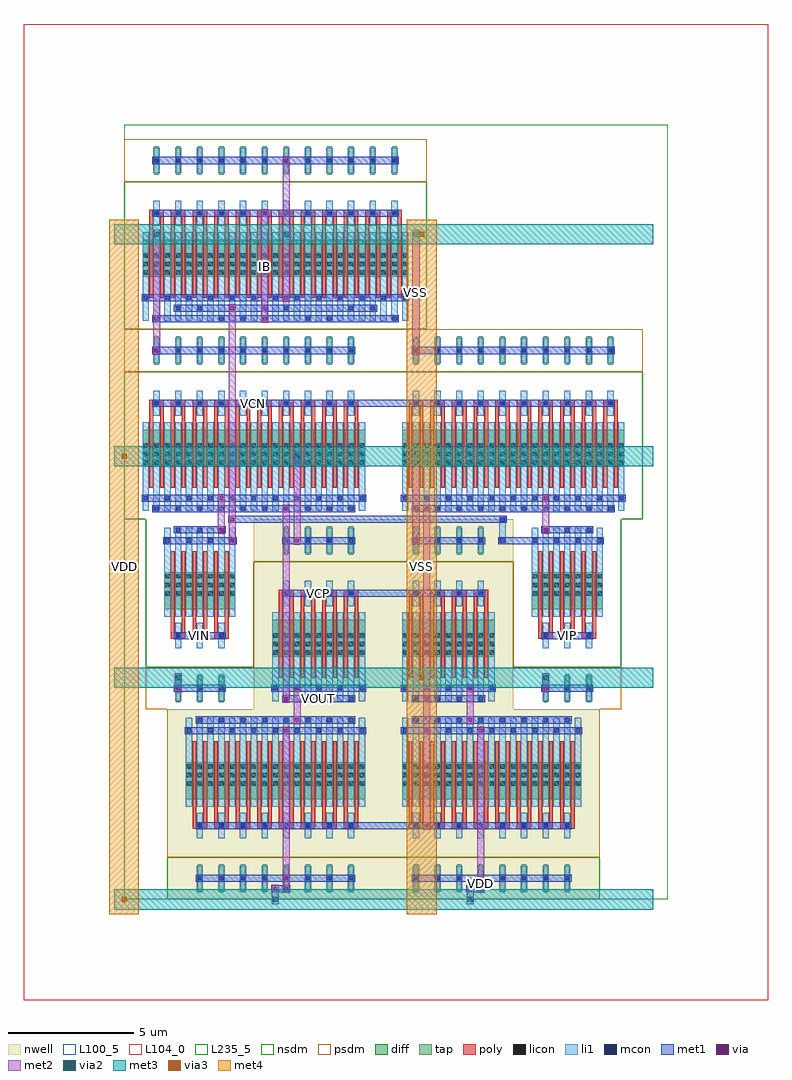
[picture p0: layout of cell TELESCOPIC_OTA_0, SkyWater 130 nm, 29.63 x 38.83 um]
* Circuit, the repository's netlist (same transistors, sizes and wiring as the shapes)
* NGSPICE file created from TELESCOPIC_OTA_0.ext - technology: sky130A

.subckt PMOS_4T_48128194_X4_Y1_1774869455 a_230_420# a_200_252# a_147_420# w_0_0#
X0 a_230_420# a_200_252# a_147_420# w_0_0# sky130_fd_pr__pfet_01v8 ad=0.2058 pd=1.75 as=0.2058 ps=1.75 w=1.47 l=0.15 M=8
.ends

.subckt NMOS_4T_31167546_X10_Y1_1774869453 a_230_420# a_200_252# a_147_420# a_241_1232#
X0 a_147_420# a_200_252# a_230_420# a_241_1232# sky130_fd_pr__nfet_01v8 ad=0.2058 pd=1.75 as=0.2058 ps=1.75 w=1.47 l=0.15 M=20
.ends

.subckt SCM_NMOS_90644832_X6_Y1_1774869457 a_402_420# a_200_252# a_147_420#
X0 a_147_420# a_200_252# a_402_420# a_147_420# sky130_fd_pr__nfet_01v8 ad=0.2058 pd=1.75 as=0.2058 ps=1.75 w=1.47 l=0.15 M=12
X1 a_147_420# a_200_252# a_200_252# a_147_420# sky130_fd_pr__nfet_01v8 ad=0.2058 pd=1.75 as=0.2058 ps=1.75 w=1.47 l=0.15 M=12
.ends

.subckt NMOS_4T_47642139_X3_Y1_1774869454 a_230_420# a_200_252# a_147_420# a_241_1232#
X0 a_147_420# a_200_252# a_230_420# a_241_1232# sky130_fd_pr__nfet_01v8 ad=0.2058 pd=1.75 as=0.2058 ps=1.75 w=1.47 l=0.15 M=6
.ends

.subckt PMOS_S_59459431_X8_Y1_1774869456 a_230_420# a_200_252# w_0_0#
X0 a_230_420# a_200_252# w_0_0# w_0_0# sky130_fd_pr__pfet_01v8 ad=0.2058 pd=1.75 as=0.2058 ps=1.75 w=1.47 l=0.15 M=16
.ends

.subckt TELESCOPIC_OTA_0 IB VCN VOUT VIP VIN VCP VSS VDD
XPMOS_4T_48128194_X4_Y1_1774869455_1 m1_2376_560# VCP m1_2720_1400# VDD PMOS_4T_48128194_X4_Y1_1774869455
XPMOS_4T_48128194_X4_Y1_1774869455_0 VOUT VCP m1_1344_1400# VDD PMOS_4T_48128194_X4_Y1_1774869455
XNMOS_4T_31167546_X10_Y1_1774869453_0 VOUT VCN m1_742_2912# VSS NMOS_4T_31167546_X10_Y1_1774869453
XNMOS_4T_31167546_X10_Y1_1774869453_1 m1_2376_560# VCN m1_3322_2912# VSS NMOS_4T_31167546_X10_Y1_1774869453
XSCM_NMOS_90644832_X6_Y1_1774869457_0 li_2985_2839# IB VSS SCM_NMOS_90644832_X6_Y1_1774869457
XNMOS_4T_47642139_X3_Y1_1774869454_0 m1_742_2912# VIN li_2985_2839# VSS NMOS_4T_47642139_X3_Y1_1774869454
XNMOS_4T_47642139_X3_Y1_1774869454_1 m1_3322_2912# VIP li_2985_2839# VSS NMOS_4T_47642139_X3_Y1_1774869454
XPMOS_S_59459431_X8_Y1_1774869456_0 m1_1344_1400# m1_2376_560# VDD PMOS_S_59459431_X8_Y1_1774869456
XPMOS_S_59459431_X8_Y1_1774869456_1 m1_2720_1400# m1_2376_560# VDD PMOS_S_59459431_X8_Y1_1774869456
.ends

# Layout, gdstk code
from math import pi, radians
import gdstk
lib = gdstk.Library(unit=1e-6, precision=1e-09)
def R(c, l, rs):  # rectangles x0, y0, x1, y1
    for r in rs: c.add(gdstk.rectangle(r[:2], r[2:], *l))
def A(c, l, x, y, w, h, nx, ny, dx, dy):  # array of equal rectangles
    R(c, l, [(x+i*dx, y+j*dy, x+i*dx+w, y+j*dy+h) for i in range(nx) for j in range(ny)])
def P(c, l, *ps):  # polygons
    for p in ps: c.add(gdstk.Polygon(p, *l))
nwell = (64, 20)
diff = (65, 20)
tap = (65, 44)
poly = (66, 20)
licon = (66, 44)
li1 = (67, 20)
mcon = (67, 44)
met1 = (68, 20)
via = (68, 44)
met2 = (69, 20)
via2 = (69, 44)
met3 = (70, 20)
via3 = (70, 44)
met4 = (71, 20)
nsdm = (93, 44)
psdm = (94, 20)
L100_5 = (100, 5)
L104_0 = (104, 0)
L235_5 = (235, 5)

scm_nmos_90644832_x6_y1_ = lib.new_cell('SCM_NMOS_90644832_X6_Y1_1774869457')
R(scm_nmos_90644832_x6_y1_, diff, [(0.735,2.1,11.305,3.57)])
A(scm_nmos_90644832_x6_y1_, tap, 1.205, 6.16, 0.17, 1.12, 12, 1, 0.86, 0)
A(scm_nmos_90644832_x6_y1_, poly, 1, 1.26, 0.15, 3.36, 24, 1, 0.43, 0)
A(scm_nmos_90644832_x6_y1_, poly, 1, 4.485, 0.58, 0.27, 12, 1, 0.86, 0)
A(scm_nmos_90644832_x6_y1_, licon, 0.775, 2.18, 0.17, 0.17, 3, 3, 0.43, 0.34)
A(scm_nmos_90644832_x6_y1_, licon, 1.635, 2.18, 0.17, 0.17, 3, 3, 0.43, 0.34)
A(scm_nmos_90644832_x6_y1_, licon, 2.495, 2.18, 0.17, 0.17, 3, 3, 0.43, 0.34)
A(scm_nmos_90644832_x6_y1_, licon, 3.355, 2.18, 0.17, 0.17, 3, 3, 0.43, 0.34)
A(scm_nmos_90644832_x6_y1_, licon, 4.215, 2.18, 0.17, 0.17, 3, 3, 0.43, 0.34)
A(scm_nmos_90644832_x6_y1_, licon, 5.075, 2.18, 0.17, 0.17, 3, 3, 0.43, 0.34)
A(scm_nmos_90644832_x6_y1_, licon, 5.935, 2.18, 0.17, 0.17, 3, 3, 0.43, 0.34)
A(scm_nmos_90644832_x6_y1_, licon, 6.795, 2.18, 0.17, 0.17, 3, 3, 0.43, 0.34)
A(scm_nmos_90644832_x6_y1_, licon, 7.655, 2.18, 0.17, 0.17, 3, 3, 0.43, 0.34)
A(scm_nmos_90644832_x6_y1_, licon, 8.515, 2.18, 0.17, 0.17, 3, 3, 0.43, 0.34)
A(scm_nmos_90644832_x6_y1_, licon, 9.375, 2.18, 0.17, 0.17, 3, 3, 0.43, 0.34)
A(scm_nmos_90644832_x6_y1_, licon, 10.235, 2.18, 0.17, 0.17, 3, 3, 0.43, 0.34)
A(scm_nmos_90644832_x6_y1_, licon, 1.205, 4.535, 0.17, 0.17, 12, 2, 0.86, 2.1)
A(scm_nmos_90644832_x6_y1_, li1, 0.735, 0.335, 0.25, 3.53, 25, 1, 0.43, 0)
A(scm_nmos_90644832_x6_y1_, li1, 1.165, 4.115, 0.25, 1.01, 12, 2, 0.86, 2.1)
A(scm_nmos_90644832_x6_y1_, mcon, 0.775, 1.175, 0.17, 0.17, 13, 1, 0.86, 0)
A(scm_nmos_90644832_x6_y1_, mcon, 1.205, 4.535, 0.17, 0.17, 12, 2, 0.86, 2.1)
R(scm_nmos_90644832_x6_y1_, mcon, [(1.205,0.335,1.375,0.505), (3.785,0.335,3.955,0.505), (4.645,0.335,4.815,0.505), (7.225,0.335,7.395,0.505), (8.085,0.335,8.255,0.505), (10.665,0.335,10.835,0.505), (2.065,0.755,2.235,0.925), (2.925,0.755,3.095,0.925), (5.505,0.755,5.675,0.925), (6.365,0.755,6.535,0.925), (8.945,0.755,9.115,0.925), (9.805,0.755,9.975,0.925)])
R(scm_nmos_90644832_x6_y1_, met1, [(1.12,0.28,10.92,0.56), (1.98,0.7,10.06,0.98), (0.69,1.12,11.35,1.4), (1.12,4.48,10.92,4.76), (1.12,6.58,10.92,6.86)])
R(scm_nmos_90644832_x6_y1_, via, [(5.515,0.345,5.665,0.495), (6.375,1.185,6.525,1.335), (5.515,4.545,5.665,4.695), (6.375,6.645,6.525,6.795)])
R(scm_nmos_90644832_x6_y1_, met2, [(5.45,0.26,5.73,4.78), (6.31,1.1,6.59,6.88)])
R(scm_nmos_90644832_x6_y1_, nsdm, [(0,0,12.04,5.88)])
R(scm_nmos_90644832_x6_y1_, psdm, [(0,5.88,12.04,7.56)])
R(scm_nmos_90644832_x6_y1_, L100_5, [(0,0,12.04,7.56)])

pmos_s_59459431_x8_y1_17 = lib.new_cell('PMOS_S_59459431_X8_Y1_1774869456')
R(pmos_s_59459431_x8_y1_17, nwell, [(0,0,8.6,7.56)])
R(pmos_s_59459431_x8_y1_17, diff, [(0.735,2.1,7.865,3.57)])
A(pmos_s_59459431_x8_y1_17, tap, 1.205, 6.16, 0.17, 1.12, 8, 1, 0.86, 0)
A(pmos_s_59459431_x8_y1_17, poly, 1, 1.26, 0.15, 3.36, 16, 1, 0.43, 0)
A(pmos_s_59459431_x8_y1_17, poly, 1, 4.485, 0.58, 0.27, 8, 1, 0.86, 0)
A(pmos_s_59459431_x8_y1_17, licon, 0.775, 2.18, 0.17, 0.17, 3, 3, 0.43, 0.34)
A(pmos_s_59459431_x8_y1_17, licon, 1.635, 2.18, 0.17, 0.17, 3, 3, 0.43, 0.34)
A(pmos_s_59459431_x8_y1_17, licon, 2.495, 2.18, 0.17, 0.17, 3, 3, 0.43, 0.34)
A(pmos_s_59459431_x8_y1_17, licon, 3.355, 2.18, 0.17, 0.17, 3, 3, 0.43, 0.34)
A(pmos_s_59459431_x8_y1_17, licon, 4.215, 2.18, 0.17, 0.17, 3, 3, 0.43, 0.34)
A(pmos_s_59459431_x8_y1_17, licon, 5.075, 2.18, 0.17, 0.17, 3, 3, 0.43, 0.34)
A(pmos_s_59459431_x8_y1_17, licon, 5.935, 2.18, 0.17, 0.17, 3, 3, 0.43, 0.34)
A(pmos_s_59459431_x8_y1_17, licon, 6.795, 2.18, 0.17, 0.17, 3, 3, 0.43, 0.34)
A(pmos_s_59459431_x8_y1_17, licon, 1.205, 4.535, 0.17, 0.17, 8, 2, 0.86, 2.1)
A(pmos_s_59459431_x8_y1_17, li1, 0.735, 0.335, 0.25, 3.53, 17, 1, 0.43, 0)
A(pmos_s_59459431_x8_y1_17, li1, 1.165, 4.115, 0.25, 1.01, 8, 2, 0.86, 2.1)
A(pmos_s_59459431_x8_y1_17, mcon, 1.205, 0.335, 0.17, 0.17, 8, 2, 0.86, 4.2)
A(pmos_s_59459431_x8_y1_17, mcon, 0.775, 0.755, 0.17, 0.17, 9, 1, 0.86, 0)
A(pmos_s_59459431_x8_y1_17, mcon, 1.205, 6.635, 0.17, 0.17, 8, 1, 0.86, 0)
R(pmos_s_59459431_x8_y1_17, met1, [(1.12,0.28,7.48,0.56), (0.69,0.7,7.91,0.98), (1.12,4.48,7.48,4.76), (1.12,6.58,7.48,6.86)])
R(pmos_s_59459431_x8_y1_17, via, [(4.655,0.765,4.805,0.915), (4.655,6.645,4.805,6.795)])
R(pmos_s_59459431_x8_y1_17, met2, [(4.59,0.68,4.87,6.88)])
R(pmos_s_59459431_x8_y1_17, nsdm, [(0,5.88,8.6,7.56)])
R(pmos_s_59459431_x8_y1_17, psdm, [(0,0,8.6,5.88)])
R(pmos_s_59459431_x8_y1_17, L100_5, [(0,0,8.6,7.56)])

nmos_4t_31167546_x10_y1_ = lib.new_cell('NMOS_4T_31167546_X10_Y1_1774869453')
R(nmos_4t_31167546_x10_y1_, diff, [(0.735,2.1,9.585,3.57)])
A(nmos_4t_31167546_x10_y1_, tap, 1.205, 6.16, 0.17, 1.12, 10, 1, 0.86, 0)
A(nmos_4t_31167546_x10_y1_, poly, 1, 1.26, 0.15, 3.36, 20, 1, 0.43, 0)
A(nmos_4t_31167546_x10_y1_, poly, 1, 4.485, 0.58, 0.27, 10, 1, 0.86, 0)
A(nmos_4t_31167546_x10_y1_, licon, 0.775, 2.18, 0.17, 0.17, 3, 3, 0.43, 0.34)
A(nmos_4t_31167546_x10_y1_, licon, 1.635, 2.18, 0.17, 0.17, 3, 3, 0.43, 0.34)
A(nmos_4t_31167546_x10_y1_, licon, 2.495, 2.18, 0.17, 0.17, 3, 3, 0.43, 0.34)
A(nmos_4t_31167546_x10_y1_, licon, 3.355, 2.18, 0.17, 0.17, 3, 3, 0.43, 0.34)
A(nmos_4t_31167546_x10_y1_, licon, 4.215, 2.18, 0.17, 0.17, 3, 3, 0.43, 0.34)
A(nmos_4t_31167546_x10_y1_, licon, 5.075, 2.18, 0.17, 0.17, 3, 3, 0.43, 0.34)
A(nmos_4t_31167546_x10_y1_, licon, 5.935, 2.18, 0.17, 0.17, 3, 3, 0.43, 0.34)
A(nmos_4t_31167546_x10_y1_, licon, 6.795, 2.18, 0.17, 0.17, 3, 3, 0.43, 0.34)
A(nmos_4t_31167546_x10_y1_, licon, 7.655, 2.18, 0.17, 0.17, 3, 3, 0.43, 0.34)
A(nmos_4t_31167546_x10_y1_, licon, 8.515, 2.18, 0.17, 0.17, 3, 3, 0.43, 0.34)
A(nmos_4t_31167546_x10_y1_, licon, 1.205, 4.535, 0.17, 0.17, 10, 2, 0.86, 2.1)
A(nmos_4t_31167546_x10_y1_, li1, 0.735, 0.335, 0.25, 3.53, 21, 1, 0.43, 0)
A(nmos_4t_31167546_x10_y1_, li1, 1.165, 4.115, 0.25, 1.01, 10, 2, 0.86, 2.1)
A(nmos_4t_31167546_x10_y1_, mcon, 1.205, 0.335, 0.17, 0.17, 10, 2, 0.86, 4.2)
A(nmos_4t_31167546_x10_y1_, mcon, 0.775, 0.755, 0.17, 0.17, 11, 1, 0.86, 0)
A(nmos_4t_31167546_x10_y1_, mcon, 1.205, 6.635, 0.17, 0.17, 10, 1, 0.86, 0)
R(nmos_4t_31167546_x10_y1_, met1, [(1.12,0.28,9.2,0.56), (0.69,0.7,9.63,0.98), (1.12,4.48,9.2,4.76), (1.12,6.58,9.2,6.86)])
R(nmos_4t_31167546_x10_y1_, nsdm, [(0,0,10.32,5.88)])
R(nmos_4t_31167546_x10_y1_, psdm, [(0,5.88,10.32,7.56)])
R(nmos_4t_31167546_x10_y1_, L100_5, [(0,0,10.32,7.56)])

nmos_4t_47642139_x3_y1_1 = lib.new_cell('NMOS_4T_47642139_X3_Y1_1774869454')
R(nmos_4t_47642139_x3_y1_1, diff, [(0.735,2.1,3.565,3.57)])
A(nmos_4t_47642139_x3_y1_1, tap, 1.205, 6.16, 0.17, 1.12, 3, 1, 0.86, 0)
A(nmos_4t_47642139_x3_y1_1, poly, 1, 1.26, 0.15, 3.36, 6, 1, 0.43, 0)
A(nmos_4t_47642139_x3_y1_1, poly, 1, 4.485, 0.58, 0.27, 3, 1, 0.86, 0)
A(nmos_4t_47642139_x3_y1_1, licon, 0.775, 2.18, 0.17, 0.17, 3, 3, 0.43, 0.34)
A(nmos_4t_47642139_x3_y1_1, licon, 1.635, 2.18, 0.17, 0.17, 3, 3, 0.43, 0.34)
A(nmos_4t_47642139_x3_y1_1, licon, 2.495, 2.18, 0.17, 0.17, 3, 3, 0.43, 0.34)
A(nmos_4t_47642139_x3_y1_1, licon, 1.205, 4.535, 0.17, 0.17, 3, 2, 0.86, 2.1)
A(nmos_4t_47642139_x3_y1_1, li1, 0.735, 0.335, 0.25, 3.53, 7, 1, 0.43, 0)
A(nmos_4t_47642139_x3_y1_1, li1, 1.165, 4.115, 0.25, 1.01, 3, 2, 0.86, 2.1)
A(nmos_4t_47642139_x3_y1_1, mcon, 1.205, 0.335, 0.17, 0.17, 3, 2, 0.86, 4.2)
A(nmos_4t_47642139_x3_y1_1, mcon, 0.775, 0.755, 0.17, 0.17, 4, 1, 0.86, 0)
A(nmos_4t_47642139_x3_y1_1, mcon, 1.205, 6.635, 0.17, 0.17, 3, 1, 0.86, 0)
R(nmos_4t_47642139_x3_y1_1, met1, [(1.12,0.28,3.18,0.56), (0.69,0.7,3.61,0.98), (1.12,4.48,3.18,4.76), (1.12,6.58,3.18,6.86)])
R(nmos_4t_47642139_x3_y1_1, nsdm, [(0,0,4.3,5.88)])
R(nmos_4t_47642139_x3_y1_1, psdm, [(0,5.88,4.3,7.56)])
R(nmos_4t_47642139_x3_y1_1, L100_5, [(0,0,4.3,7.56)])

pmos_4t_48128194_x4_y1_1 = lib.new_cell('PMOS_4T_48128194_X4_Y1_1774869455')
R(pmos_4t_48128194_x4_y1_1, nwell, [(0,0,5.16,7.56)])
R(pmos_4t_48128194_x4_y1_1, diff, [(0.735,2.1,4.425,3.57)])
A(pmos_4t_48128194_x4_y1_1, tap, 1.205, 6.16, 0.17, 1.12, 4, 1, 0.86, 0)
A(pmos_4t_48128194_x4_y1_1, poly, 1, 1.26, 0.15, 3.36, 8, 1, 0.43, 0)
A(pmos_4t_48128194_x4_y1_1, poly, 1, 4.485, 0.58, 0.27, 4, 1, 0.86, 0)
A(pmos_4t_48128194_x4_y1_1, licon, 0.775, 2.18, 0.17, 0.17, 3, 3, 0.43, 0.34)
A(pmos_4t_48128194_x4_y1_1, licon, 1.635, 2.18, 0.17, 0.17, 3, 3, 0.43, 0.34)
A(pmos_4t_48128194_x4_y1_1, licon, 2.495, 2.18, 0.17, 0.17, 3, 3, 0.43, 0.34)
A(pmos_4t_48128194_x4_y1_1, licon, 3.355, 2.18, 0.17, 0.17, 3, 3, 0.43, 0.34)
A(pmos_4t_48128194_x4_y1_1, licon, 1.205, 4.535, 0.17, 0.17, 4, 2, 0.86, 2.1)
A(pmos_4t_48128194_x4_y1_1, li1, 0.735, 0.335, 0.25, 3.53, 9, 1, 0.43, 0)
A(pmos_4t_48128194_x4_y1_1, li1, 1.165, 4.115, 0.25, 1.01, 4, 2, 0.86, 2.1)
A(pmos_4t_48128194_x4_y1_1, mcon, 1.205, 0.335, 0.17, 0.17, 4, 2, 0.86, 4.2)
A(pmos_4t_48128194_x4_y1_1, mcon, 0.775, 0.755, 0.17, 0.17, 5, 1, 0.86, 0)
A(pmos_4t_48128194_x4_y1_1, mcon, 1.205, 6.635, 0.17, 0.17, 4, 1, 0.86, 0)
R(pmos_4t_48128194_x4_y1_1, met1, [(1.12,0.28,4.04,0.56), (0.69,0.7,4.47,0.98), (1.12,4.48,4.04,4.76), (1.12,6.58,4.04,6.86)])
R(pmos_4t_48128194_x4_y1_1, nsdm, [(0,5.88,5.16,7.56)])
R(pmos_4t_48128194_x4_y1_1, psdm, [(0,0,5.16,5.88)])
R(pmos_4t_48128194_x4_y1_1, L100_5, [(0,0,5.16,7.56)])

telescopic_ota_0 = lib.new_cell('TELESCOPIC_OTA_0')
R(telescopic_ota_0, li1, [(14.925,14.195,15.175,14.365), (14.925,14.195,15.175,14.365), (14.925,14.28,15.175,15.12), (14.925,15.035,15.175,15.205), (14.925,15.035,15.175,15.205)])
R(telescopic_ota_0, mcon, [(14.965,14.195,15.135,14.365), (14.965,14.195,15.135,14.365), (14.965,15.035,15.135,15.205), (14.965,15.035,15.135,15.205)])
R(telescopic_ota_0, met1, [(5.86,0.28,6.18,0.56), (5.86,0.28,6.18,0.56), (5.86,0.28,6.18,0.56), (5.86,0.28,6.18,0.56), (6.02,0.28,6.45,0.56), (6.29,0.28,6.61,0.56), (6.29,0.28,6.61,0.56), (6.29,0.28,6.61,0.56), (6.29,0.28,6.61,0.56), (13.6,0.28,13.92,0.56), (13.6,0.28,13.92,0.56), (13.6,0.28,13.92,0.56), (13.6,0.28,13.92,0.56), (13.6,0.28,13.92,0.56), (13.76,0.28,14.19,0.56), (14.03,0.28,14.35,0.56), (14.03,0.28,14.35,0.56), (14.03,0.28,14.35,0.56), (14.03,0.28,14.35,0.56), (14.03,0.28,14.35,0.56), (9.03,2.8,11.61,3.08), (11.88,2.8,12.2,3.08), (11.88,2.8,12.2,3.08), (11.88,2.8,12.2,3.08), (11.88,2.8,12.2,3.08), (6.72,7,7.04,7.28), (6.72,7,7.04,7.28), (13.6,7,13.92,7.28), (13.6,7,13.92,7.28), (6.29,7.84,6.61,8.12), (6.29,7.84,6.61,8.12), (11.88,7.84,12.2,8.12), (11.88,7.84,12.2,8.12), (11.88,7.84,12.2,8.12), (11.88,7.84,12.2,8.12), (1.99,8.26,2.31,8.54), (1.99,8.26,2.31,8.54), (6.72,8.26,7.04,8.54), (6.72,8.26,7.04,8.54), (13.6,8.26,13.92,8.54), (13.6,8.26,13.92,8.54), (16.61,8.26,16.93,8.54), (16.61,8.26,16.93,8.54), (16.61,8.26,16.93,8.54), (9.03,12.04,11.61,12.32), (4.14,14.14,4.46,14.42), (4.14,14.14,4.46,14.42), (4.14,14.14,4.46,14.42), (4.14,14.14,4.46,14.42), (6.72,14.14,7.04,14.42), (6.72,14.14,7.04,14.42), (11.45,14.14,11.77,14.42), (11.45,14.14,11.77,14.42), (11.45,14.14,11.77,14.42), (14.88,14.14,15.22,14.42), (14.88,14.14,15.22,14.42), (15.05,14.14,16.34,14.42), (3.71,14.56,4.03,14.84), (3.71,14.56,4.03,14.84), (16.61,14.56,16.93,14.84), (16.61,14.56,16.93,14.84), (4.14,14.98,4.46,15.26), (4.14,14.98,4.46,15.26), (4.3,14.98,15.05,15.26), (14.88,14.98,15.22,15.26), (14.88,14.98,15.22,15.26), (6.29,15.4,6.61,15.68), (6.29,15.4,6.61,15.68), (11.88,15.4,12.2,15.68), (11.88,15.4,12.2,15.68), (3.71,15.82,4.03,16.1), (3.71,15.82,4.03,16.1), (16.61,15.82,16.93,16.1), (16.61,15.82,16.93,16.1), (9.03,19.6,11.61,19.88), (1.13,21.7,1.45,21.98), (1.13,21.7,1.45,21.98), (1.13,21.7,1.45,21.98), (1.13,21.7,1.45,21.98), (11.45,21.7,11.77,21.98), (11.45,21.7,11.77,21.98), (11.45,21.7,11.77,21.98), (11.45,21.7,11.77,21.98), (11.45,21.7,11.77,21.98), (4.14,23.38,4.46,23.66), (4.14,23.38,4.46,23.66), (4.14,23.38,4.46,23.66), (4.14,23.38,4.46,23.66)])
P(telescopic_ota_0, met1, [(0,0),(0,0),(0,0),(0,0)],
  [(0,0),(0,0),(0,0),(0,0)],
  [(0,0),(0,0),(0,0),(0,0)],
  [(0,0),(0,0),(0,0),(0,0)],
  [(0,0),(0,0),(0,0),(0,0)],
  [(0,0),(0,0),(0,0),(0,0)],
  [(0,0),(0,0),(0,0),(0,0)],
  [(0,0),(0,0),(0,0),(0,0)],
  [(0,0),(0,0),(0,0),(0,0)],
  [(0,0),(0,0),(0,0),(0,0)],
  [(0,0),(0,0),(0,0),(0,0)],
  [(0,0),(0,0),(0,0),(0,0)],
  [(0,0),(0,0),(0,0),(0,0)],
  [(0,0),(0,0),(0,0),(0,0)],
  [(0,0),(0,0),(0,0),(0,0)],
  [(0,0),(0,0),(0,0),(0,0)],
  [(0,0),(0,0),(0,0),(0,0)],
  [(0,0),(0,0),(0,0),(0,0)],
  [(0,0),(0,0),(0,0),(0,0)],
  [(0,0),(0,0),(0,0),(0,0)],
  [(0,0),(0,0),(0,0),(0,0)],
  [(0,0),(0,0),(0,0),(0,0)],
  [(0,0),(0,0),(0,0),(0,0)],
  [(0,0),(0,0),(0,0),(0,0)],
  [(0,0),(0,0),(0,0),(0,0)],
  [(0,0),(0,0),(0,0),(0,0)],
  [(0,0),(0,0),(0,0),(0,0)],
  [(0,0),(0,0),(0,0),(0,0)],
  [(0,0),(0,0),(0,0),(0,0)],
  [(0,0),(0,0),(0,0),(0,0)],
  [(0,0),(0,0),(0,0),(0,0)],
  [(0,0),(0,0),(0,0),(0,0)],
  [(0,0),(0,0),(0,0),(0,0)],
  [(0,0),(0,0),(0,0),(0,0)])
R(telescopic_ota_0, via, [(5.945,0.345,6.095,0.495), (5.945,0.345,6.095,0.495), (5.945,0.345,6.095,0.495), (5.945,0.345,6.095,0.495), (6.375,0.345,6.525,0.495), (6.375,0.345,6.525,0.495), (6.375,0.345,6.525,0.495), (6.375,0.345,6.525,0.495), (13.685,0.345,13.835,0.495), (13.685,0.345,13.835,0.495), (13.685,0.345,13.835,0.495), (13.685,0.345,13.835,0.495), (13.685,0.345,13.835,0.495), (14.115,0.345,14.265,0.495), (14.115,0.345,14.265,0.495), (14.115,0.345,14.265,0.495), (14.115,0.345,14.265,0.495), (14.115,0.345,14.265,0.495), (11.965,2.865,12.115,3.015), (11.965,2.865,12.115,3.015), (11.965,2.865,12.115,3.015), (11.965,2.865,12.115,3.015), (6.805,7.065,6.955,7.215), (6.805,7.065,6.955,7.215), (13.685,7.065,13.835,7.215), (13.685,7.065,13.835,7.215), (6.375,7.905,6.525,8.055), (6.375,7.905,6.525,8.055), (11.965,7.905,12.115,8.055), (11.965,7.905,12.115,8.055), (11.965,7.905,12.115,8.055), (11.965,7.905,12.115,8.055), (2.075,8.325,2.225,8.475), (2.075,8.325,2.225,8.475), (6.805,8.325,6.955,8.475), (6.805,8.325,6.955,8.475), (13.685,8.325,13.835,8.475), (13.685,8.325,13.835,8.475), (16.695,8.325,16.845,8.475), (16.695,8.325,16.845,8.475), (16.695,8.325,16.845,8.475), (4.225,14.205,4.375,14.355), (4.225,14.205,4.375,14.355), (4.225,14.205,4.375,14.355), (4.225,14.205,4.375,14.355), (6.805,14.205,6.955,14.355), (6.805,14.205,6.955,14.355), (11.535,14.205,11.685,14.355), (11.535,14.205,11.685,14.355), (11.535,14.205,11.685,14.355), (3.795,14.625,3.945,14.775), (3.795,14.625,3.945,14.775), (16.695,14.625,16.845,14.775), (16.695,14.625,16.845,14.775), (4.225,15.045,4.375,15.195), (4.225,15.045,4.375,15.195), (6.375,15.465,6.525,15.615), (6.375,15.465,6.525,15.615), (11.965,15.465,12.115,15.615), (11.965,15.465,12.115,15.615), (3.795,15.885,3.945,16.035), (3.795,15.885,3.945,16.035), (16.695,15.885,16.845,16.035), (16.695,15.885,16.845,16.035), (1.215,21.765,1.365,21.915), (1.215,21.765,1.365,21.915), (1.215,21.765,1.365,21.915), (1.215,21.765,1.365,21.915), (11.535,21.765,11.685,21.915), (11.535,21.765,11.685,21.915), (11.535,21.765,11.685,21.915), (11.535,21.765,11.685,21.915), (11.535,21.765,11.685,21.915), (4.225,23.445,4.375,23.595), (4.225,23.445,4.375,23.595), (4.225,23.445,4.375,23.595), (4.225,23.445,4.375,23.595)])
R(telescopic_ota_0, met2, [(5.88,-0.185,6.16,0.185), (5.88,-0.185,6.16,0.185), (5.88,-0.185,6.16,0.185), (5.88,-0.185,6.16,0.185), (13.62,-0.185,13.9,0.185), (13.62,-0.185,13.9,0.185), (13.62,-0.185,13.9,0.185), (13.62,-0.185,13.9,0.185), (13.62,-0.185,13.9,0.185), (5.88,0,6.16,0.42), (13.62,0,13.9,0.42), (5.88,0.26,6.16,0.58), (5.88,0.26,6.16,0.58), (5.88,0.26,6.16,0.58), (5.88,0.26,6.16,0.58), (6.31,0.26,6.59,0.58), (6.31,0.26,6.59,0.58), (6.31,0.26,6.59,0.58), (6.31,0.26,6.59,0.58), (13.62,0.26,13.9,0.58), (13.62,0.26,13.9,0.58), (13.62,0.26,13.9,0.58), (13.62,0.26,13.9,0.58), (13.62,0.26,13.9,0.58), (14.05,0.26,14.33,0.58), (14.05,0.26,14.33,0.58), (14.05,0.26,14.33,0.58), (14.05,0.26,14.33,0.58), (14.05,0.26,14.33,0.58), (6.31,0.42,6.59,0.84), (14.05,0.42,14.33,0.84), (11.9,2.78,12.18,3.1), (11.9,2.78,12.18,3.1), (11.9,2.78,12.18,3.1), (11.9,2.78,12.18,3.1), (11.9,2.94,12.18,7.98), (6.74,6.98,7.02,7.3), (6.74,6.98,7.02,7.3), (13.62,6.98,13.9,7.3), (13.62,6.98,13.9,7.3), (6.74,7.14,7.02,8.4), (13.62,7.14,13.9,8.4), (6.31,7.82,6.59,8.14), (6.31,7.82,6.59,8.14), (11.9,7.82,12.18,8.14), (11.9,7.82,12.18,8.14), (11.9,7.82,12.18,8.14), (11.9,7.82,12.18,8.14), (6.31,7.98,6.59,15.54), (11.9,7.98,12.18,15.54), (2.01,8.24,2.29,8.56), (2.01,8.24,2.29,8.56), (6.74,8.24,7.02,8.56), (6.74,8.24,7.02,8.56), (13.62,8.24,13.9,8.56), (13.62,8.24,13.9,8.56), (16.63,8.24,16.91,8.56), (16.63,8.24,16.91,8.56), (16.63,8.24,16.91,8.56), (2.01,8.4,2.29,8.82), (16.63,8.4,16.91,8.82), (2.01,8.635,2.29,9.005), (2.01,8.635,2.29,9.005), (16.63,8.635,16.91,9.005), (16.63,8.635,16.91,9.005), (16.63,8.635,16.91,9.005), (4.16,14.12,4.44,14.44), (4.16,14.12,4.44,14.44), (4.16,14.12,4.44,14.44), (4.16,14.12,4.44,14.44), (6.74,14.12,7.02,14.44), (6.74,14.12,7.02,14.44), (11.47,14.12,11.75,14.44), (11.47,14.12,11.75,14.44), (11.47,14.12,11.75,14.44), (4.16,14.28,4.44,23.52), (6.74,14.28,7.02,17.64), (11.47,14.28,11.75,17.64), (3.73,14.54,4.01,14.86), (3.73,14.54,4.01,14.86), (16.63,14.54,16.91,14.86), (16.63,14.54,16.91,14.86), (3.73,14.7,4.01,15.96), (16.63,14.7,16.91,15.96), (4.16,14.96,4.44,15.28), (4.16,14.96,4.44,15.28), (6.31,15.38,6.59,15.7), (6.31,15.38,6.59,15.7), (11.9,15.38,12.18,15.7), (11.9,15.38,12.18,15.7), (3.73,15.8,4.01,16.12), (3.73,15.8,4.01,16.12), (16.63,15.8,16.91,16.12), (16.63,15.8,16.91,16.12), (6.74,17.455,7.02,17.825), (6.74,17.455,7.02,17.825), (11.47,17.455,11.75,17.825), (11.47,17.455,11.75,17.825), (11.47,17.455,11.75,17.825), (1.15,21.68,1.43,22), (1.15,21.68,1.43,22), (1.15,21.68,1.43,22), (1.15,21.68,1.43,22), (11.47,21.68,11.75,22), (11.47,21.68,11.75,22), (11.47,21.68,11.75,22), (11.47,21.68,11.75,22), (11.47,21.68,11.75,22), (1.15,21.84,1.43,26.46), (11.47,21.84,11.75,26.46), (4.16,23.36,4.44,23.68), (4.16,23.36,4.44,23.68), (4.16,23.36,4.44,23.68), (4.16,23.36,4.44,23.68), (1.15,26.275,1.43,26.645), (1.15,26.275,1.43,26.645), (1.15,26.275,1.43,26.645), (1.15,26.275,1.43,26.645), (6.31,26.275,6.59,26.645), (6.31,26.275,6.59,26.645), (6.31,26.275,6.59,26.645), (6.31,26.275,6.59,26.645), (6.31,26.275,6.59,26.645), (6.31,26.275,6.59,26.645), (11.47,26.275,11.75,26.645), (11.47,26.275,11.75,26.645), (11.47,26.275,11.75,26.645), (11.47,26.275,11.75,26.645), (11.47,26.275,11.75,26.645)])
P(telescopic_ota_0, met2, [(0,0),(0,0),(0,0),(0,0)],
  [(0,0),(0,0),(0,0),(0,0)],
  [(0,0),(0,0),(0,0),(0,0)],
  [(0,0),(0,0),(0,0),(0,0)],
  [(0,0),(0,0),(0,0),(0,0)])
R(telescopic_ota_0, via2, [(5.92,-0.1,6.12,0.1), (5.92,-0.1,6.12,0.1), (5.92,-0.1,6.12,0.1), (5.92,-0.1,6.12,0.1), (13.66,-0.1,13.86,0.1), (13.66,-0.1,13.86,0.1), (13.66,-0.1,13.86,0.1), (13.66,-0.1,13.86,0.1), (13.66,-0.1,13.86,0.1), (2.05,8.72,2.25,8.92), (2.05,8.72,2.25,8.92), (16.67,8.72,16.87,8.92), (16.67,8.72,16.87,8.92), (16.67,8.72,16.87,8.92), (6.78,17.54,6.98,17.74), (6.78,17.54,6.98,17.74), (11.51,17.54,11.71,17.74), (11.51,17.54,11.71,17.74), (11.51,17.54,11.71,17.74), (1.19,26.36,1.39,26.56), (1.19,26.36,1.39,26.56), (1.19,26.36,1.39,26.56), (1.19,26.36,1.39,26.56), (6.35,26.36,6.55,26.56), (6.35,26.36,6.55,26.56), (6.35,26.36,6.55,26.56), (6.35,26.36,6.55,26.56), (6.35,26.36,6.55,26.56), (6.35,26.36,6.55,26.56), (11.51,26.36,11.71,26.56), (11.51,26.36,11.71,26.56), (11.51,26.36,11.71,26.56), (11.51,26.36,11.71,26.56), (11.51,26.36,11.71,26.56)])
A(telescopic_ota_0, met3, -0.4, -0.4, 4.24, 0.8, 3, 4, 3.44, 8.82)
A(telescopic_ota_0, met3, 9.92, -0.4, 2.32, 0.8, 1, 4, 0, 8.82)
A(telescopic_ota_0, met3, 11.44, -0.4, 2.72, 0.8, 1, 4, 0, 8.82)
A(telescopic_ota_0, met3, 13.36, -0.4, 4.24, 0.8, 1, 4, 0, 8.82)
A(telescopic_ota_0, met3, 16.8, -0.4, 4.24, 0.8, 1, 4, 0, 8.82)
R(telescopic_ota_0, met3, [(-0.165,-0.4,0.165,0.4), (5.855,-0.4,6.185,0.4), (5.855,-0.4,6.185,0.4), (5.855,-0.4,6.185,0.4), (5.855,-0.4,6.185,0.4), (13.595,-0.4,13.925,0.4), (13.595,-0.4,13.925,0.4), (13.595,-0.4,13.925,0.4), (13.595,-0.4,13.925,0.4), (13.595,-0.4,13.925,0.4), (1.985,8.42,2.315,9.22), (1.985,8.42,2.315,9.22), (11.675,8.42,12.005,9.22), (16.605,8.42,16.935,9.22), (16.605,8.42,16.935,9.22), (16.605,8.42,16.935,9.22), (-0.165,17.24,0.165,18.04), (6.715,17.24,7.045,18.04), (6.715,17.24,7.045,18.04), (11.445,17.24,11.775,18.04), (11.445,17.24,11.775,18.04), (11.445,17.24,11.775,18.04), (1.125,26.06,1.455,26.86), (1.125,26.06,1.455,26.86), (1.125,26.06,1.455,26.86), (1.125,26.06,1.455,26.86), (6.285,26.06,6.615,26.86), (6.285,26.06,6.615,26.86), (6.285,26.06,6.615,26.86), (6.285,26.06,6.615,26.86), (6.285,26.06,6.615,26.86), (6.285,26.06,6.615,26.86), (11.445,26.06,11.775,26.86), (11.445,26.06,11.775,26.86), (11.445,26.06,11.775,26.86), (11.445,26.06,11.775,26.86), (11.445,26.06,11.775,26.86), (11.675,26.06,12.005,26.86)])
R(telescopic_ota_0, via3, [(-0.1,-0.1,0.1,0.1), (11.74,8.72,11.94,8.92), (-0.1,17.54,0.1,17.74), (11.74,26.36,11.94,26.56)])
A(telescopic_ota_0, met4, -0.59, -0.59, 1.18, 10, 1, 3, 0, 8.82)
A(telescopic_ota_0, met4, 11.25, -0.59, 1.18, 10, 1, 3, 0, 8.82)
R(telescopic_ota_0, met4, [(-0.59,-0.165,0.59,0.165), (11.25,8.655,12.43,8.985), (-0.59,17.475,0.59,17.805), (11.25,26.295,12.43,26.625)])
R(telescopic_ota_0, L104_0, [(-4,-4,25.63,34.83)])
R(telescopic_ota_0, L235_5, [(0,0,21.63,30.83)])
telescopic_ota_0.add(gdstk.Reference(scm_nmos_90644832_x6_y1_, (0,22.68)))
telescopic_ota_0.add(gdstk.Reference(pmos_s_59459431_x8_y1_17, (18.92,7.56), rotation=pi))
telescopic_ota_0.add(gdstk.Reference(pmos_s_59459431_x8_y1_17, (1.72,7.56), x_reflection=True))
telescopic_ota_0.add(gdstk.Reference(nmos_4t_31167546_x10_y1_, (10.32,15.12)))
telescopic_ota_0.add(gdstk.Reference(nmos_4t_31167546_x10_y1_, (10.32,15.12), rotation=pi, x_reflection=True))
telescopic_ota_0.add(gdstk.Reference(nmos_4t_47642139_x3_y1_1, (15.48,15.12), x_reflection=True))
telescopic_ota_0.add(gdstk.Reference(nmos_4t_47642139_x3_y1_1, (5.16,15.12), rotation=pi))
telescopic_ota_0.add(gdstk.Reference(pmos_4t_48128194_x4_y1_1, (15.48,7.56), rotation=pi, x_reflection=True))
telescopic_ota_0.add(gdstk.Reference(pmos_4t_48128194_x4_y1_1, (5.16,7.56)))
telescopic_ota_0.add(gdstk.Label('IB', (5.59,25.2), layer=69, texttype=5))
telescopic_ota_0.add(gdstk.Label('VCN', (5.16,19.74), layer=68, texttype=5))
telescopic_ota_0.add(gdstk.Label('VOUT', (7.74,7.98), layer=68, texttype=5))
telescopic_ota_0.add(gdstk.Label('VIP', (17.63,10.5), layer=68, texttype=5))
telescopic_ota_0.add(gdstk.Label('VIN', (3.01,10.5), layer=68, texttype=5))
telescopic_ota_0.add(gdstk.Label('VCP', (7.74,12.18), layer=68, texttype=5))
telescopic_ota_0.add(gdstk.Label('VSS', (11.84,13.23), layer=71, texttype=5))
telescopic_ota_0.add(gdstk.Label('VSS', (11.84,13.23), layer=71, texttype=5))
telescopic_ota_0.add(gdstk.Label('VSS', (11.84,13.23), layer=71, texttype=5))
telescopic_ota_0.add(gdstk.Label('VSS', (11.61,24.15), layer=69, texttype=5))
telescopic_ota_0.add(gdstk.Label('VSS', (11.84,13.23), layer=71, texttype=5))
telescopic_ota_0.add(gdstk.Label('VSS', (11.84,13.23), layer=71, texttype=5))
telescopic_ota_0.add(gdstk.Label('VSS', (11.84,13.23), layer=71, texttype=5))
telescopic_ota_0.add(gdstk.Label('VSS', (11.84,13.23), layer=71, texttype=5))
telescopic_ota_0.add(gdstk.Label('VSS', (11.84,13.23), layer=71, texttype=5))
telescopic_ota_0.add(gdstk.Label('VSS', (11.84,13.23), layer=71, texttype=5))
telescopic_ota_0.add(gdstk.Label('VSS', (11.84,13.23), layer=71, texttype=5))
telescopic_ota_0.add(gdstk.Label('VSS', (11.84,13.23), layer=71, texttype=5))
telescopic_ota_0.add(gdstk.Label('VSS', (11.84,13.23), layer=71, texttype=5))
telescopic_ota_0.add(gdstk.Label('VSS', (11.84,13.23), layer=71, texttype=5))
telescopic_ota_0.add(gdstk.Label('VSS', (11.84,13.23), layer=71, texttype=5))
telescopic_ota_0.add(gdstk.Label('VDD', (14.19,0.63), layer=69, texttype=5))
telescopic_ota_0.add(gdstk.Label('VDD', (0,13.23), layer=71, texttype=5))
telescopic_ota_0.add(gdstk.Label('VDD', (0,13.23), layer=71, texttype=5))
telescopic_ota_0.add(gdstk.Label('VDD', (0,13.23), layer=71, texttype=5))
telescopic_ota_0.add(gdstk.Label('VDD', (0,13.23), layer=71, texttype=5))
telescopic_ota_0.add(gdstk.Label('VDD', (0,13.23), layer=71, texttype=5))
telescopic_ota_0.add(gdstk.Label('VDD', (0,13.23), layer=71, texttype=5))
telescopic_ota_0.add(gdstk.Label('VDD', (0,13.23), layer=71, texttype=5))
telescopic_ota_0.add(gdstk.Label('VDD', (0,13.23), layer=71, texttype=5))
telescopic_ota_0.add(gdstk.Label('VDD', (0,13.23), layer=71, texttype=5))
telescopic_ota_0.add(gdstk.Label('VDD', (0,13.23), layer=71, texttype=5))
telescopic_ota_0.add(gdstk.Label('VDD', (0,13.23), layer=71, texttype=5))
telescopic_ota_0.add(gdstk.Label('VDD', (0,13.23), layer=71, texttype=5))
telescopic_ota_0.add(gdstk.Label('VDD', (0,13.23), layer=71, texttype=5))
telescopic_ota_0.add(gdstk.Label('VDD', (0,13.23), layer=71, texttype=5))

lib.write_gds('TELESCOPIC_OTA_0.gds')
